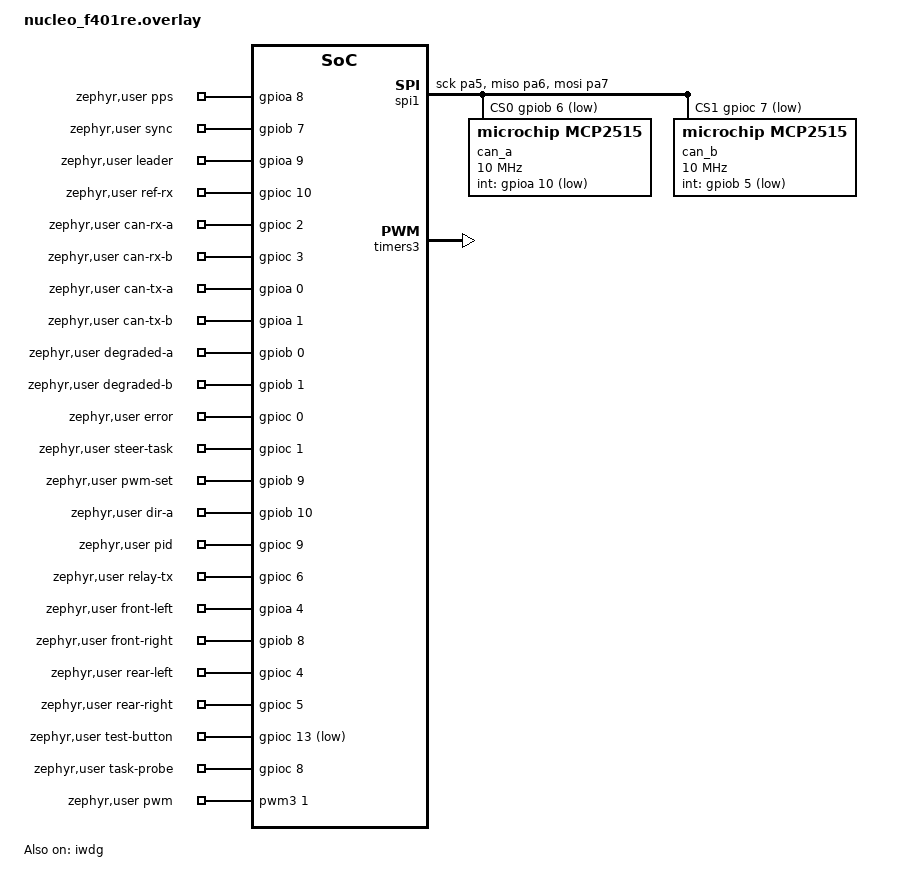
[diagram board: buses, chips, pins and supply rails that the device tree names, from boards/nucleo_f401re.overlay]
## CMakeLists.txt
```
cmake_minimum_required(VERSION 3.28.0)
find_package(Zephyr REQUIRED HINTS $ENV{ZEPHYR_BASE})
project(lab5)
get_filename_component(team_root "${CMAKE_CURRENT_SOURCE_DIR}/../.." ABSOLUTE)
set(lab5 "${team_root}/lab5")
set_property(DIRECTORY APPEND PROPERTY CMAKE_CONFIGURE_DEPENDS "${lab5}/config.json")
execute_process(COMMAND ${PYTHON_EXECUTABLE} "${lab5}/generate_config.py"
    --output "${CMAKE_CURRENT_BINARY_DIR}/lab5_config.h" COMMAND_ERROR_IS_FATAL ANY)
target_include_directories(app PRIVATE "${lab5}/core" "${CMAKE_CURRENT_BINARY_DIR}")
target_sources(app PRIVATE src/lab5_runtime.c "${lab5}/core/lab5.c" "${lab5}/core/clock.c"
    "${lab5}/core/store.c" "${lab5}/core/wire.c" "${lab5}/core/agent.c")
# Reuse the measured baseline's timing instrumentation and workloads, not copies.
set(baseline "${team_root}/lab3_wcet_baseline/lab3_wcet_baseline/stm32_zephyr/src")
target_sources(app PRIVATE src/main.c src/can_protocol.c src/frame_history.c
    src/zone_state.c src/timing_trace.c "${baseline}/timing_stats.c" "${baseline}/timing_probe.c")
target_include_directories(app PRIVATE src "${baseline}")
if(CONFIG_LAB3_ZONE_N3)
    # Lab 2 PID calculation on synthetic samples; no encoder or motor driver.
    set(lab2_pid "${team_root}/bringup/motor_test/src")
    target_sources(app PRIVATE "${baseline}/pid_measurement.c" "${lab2_pid}/velocity_control.c")
    target_include_directories(app PRIVATE "${lab2_pid}")
endif()
if(CONFIG_LAB3_ZONE_N2)
    # Lab 2 calibrated servo mapping from the tracked endpoints.
    set(calibration_file "${team_root}/config/servo_calibration.json")
    set_property(DIRECTORY APPEND PROPERTY CMAKE_CONFIGURE_DEPENDS "${calibration_file}")
    file(READ "${calibration_file}" calibration_json)
    foreach(point LEFT CENTER RIGHT)
        string(TOLOWER "${point}" key)
        string(JSON SERVO_${point}_US GET "${calibration_json}" "${key}_us")
        if(NOT "${SERVO_${point}_US}" MATCHES "^[0-9]+$" OR
           SERVO_${point}_US LESS 500 OR SERVO_${point}_US GREATER 2500)
            message(FATAL_ERROR "Invalid ${key} steering calibration")
        endif()
    endforeach()
    if(NOT ((SERVO_LEFT_US LESS SERVO_CENTER_US AND SERVO_CENTER_US LESS SERVO_RIGHT_US) OR
            (SERVO_LEFT_US GREATER SERVO_CENTER_US AND SERVO_CENTER_US GREATER SERVO_RIGHT_US)))
        message(FATAL_ERROR "Steering center must be between endpoints")
    endif()
    configure_file("${team_root}/stm32_zephyr/src/servo_calibration.h.in"
                   generated/servo_calibration.h @ONLY)
    target_sources(app PRIVATE "${baseline}/steering_measurement.c" "${team_root}/stm32_zephyr/src/servo_core.c")
    target_include_directories(app PRIVATE "${team_root}/stm32_zephyr/src"
                               "${CMAKE_CURRENT_BINARY_DIR}/generated")
endif()
```

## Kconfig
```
mainmenu "Lab 5 time and consensus"
source "Kconfig.zephyr"

config LAB3_ZONE_N2
    bool "Build front steering zone N2"
    help
      SRV servo PWM, front blinkers, FORCE_TX and the RELAY task.

config LAB3_ZONE_N3
    bool "Build rear drivetrain zone N3"
    help
      PWM_OUT motor PWM, DIR_A, PWM_SET, PID workload and rear blinkers.

config LAB3_RELAY
    bool
    default n
    help
      Keep disabled: Lab 5's consensus/discovery relay replaces the Lab 3 relay.

config LAB3_SWAP_CAN_AB
    bool "Logical bus A uses the module on CS PC7 / INT PB5"
    help
      Set for a board whose module A (CS PB6 / INT PA10) is wired to the
      physical bus the other nodes call B. Test points, DEG LEDs and
      heartbeat health bits then follow the physical bus labels.
```

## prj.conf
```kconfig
CONFIG_CAN=y
CONFIG_CAN_INIT_PRIORITY=80
CONFIG_GPIO=y
CONFIG_HWINFO=y
CONFIG_PWM=y
CONFIG_SERIAL=y
CONFIG_CONSOLE=y
CONFIG_UART_CONSOLE=y
CONFIG_PRINTK=y
CONFIG_MAIN_STACK_SIZE=2048
CONFIG_SYSTEM_WORKQUEUE_STACK_SIZE=2048
CONFIG_SYS_CLOCK_TICKS_PER_SEC=10000
CONFIG_CORTEX_M_SYSTICK_64BIT_CYCLE_COUNTER=y
CONFIG_FLASH=y
CONFIG_FLASH_MAP=y
CONFIG_FLASH_LOAD_SIZE=0x40000
CONFIG_POSIX_SYSTEM_INTERFACES=y
CONFIG_POSIX_TIMERS=y
CONFIG_ASSERT=y
CONFIG_WATCHDOG=y
# Main installs the 1 s timeout; avoid the driver's separate boot-time timeout.
CONFIG_WDT_DISABLE_AT_BOOT=y
CONFIG_SPI=y
# Poll short MCP2515 transfers (measured faster than interrupt mode on Oct 21).
CONFIG_SPI_STM32_INTERRUPT=n
CONFIG_CAN_MCP2515=y
CONFIG_CAN_DEFAULT_BITRATE=500000
# One filter per catalog ID, for each controller.
CONFIG_CAN_MAX_FILTER=8
CONFIG_CAN_MCP2515_INT_THREAD_PRIO=2
CONFIG_SHELL=y
CONFIG_SHELL_STACK_SIZE=2048
CONFIG_THREAD_NAME=y
# Crash reports: register dump plus a logged coredump on the serial console.
CONFIG_FAULT_DUMP=2
CONFIG_DEBUG_COREDUMP=y
CONFIG_DEBUG_COREDUMP_BACKEND_LOGGING=y
CONFIG_DEBUG_COREDUMP_MEMORY_DUMP_MIN=y
CONFIG_LOG_PRINTK=n
```

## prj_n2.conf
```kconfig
CONFIG_LAB3_ZONE_N2=y
```

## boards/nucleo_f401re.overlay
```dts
/* Lab 3 Part 5 demo, shared by N2 and N3. Pin record: doc/LAB3_PINOUT.md.
 * CAN modules: SPI1 PA5/PA6/PA7 (XIAO D8 SCK, D9 MISO, D10 MOSI per the
 * handout erratum); module A CS PB6 / INT PA10, module B CS PC7 / INT PB5.
 * CONFIG_LAB3_SWAP_CAN_AB maps logical bus A to module B for a board whose
 * modules are wired to the opposite physical buses.
 */
#include <zephyr/dt-bindings/gpio/gpio.h>
#include <zephyr/dt-bindings/pwm/pwm.h>

/ {
    aliases { can-a = &can_a; can-b = &can_b; };
    zephyr,user {
        pps-gpios = <&gpioa 8 GPIO_ACTIVE_HIGH>;
        sync-gpios = <&gpiob 7 GPIO_ACTIVE_HIGH>;
        leader-gpios = <&gpioa 9 GPIO_ACTIVE_HIGH>;
        ref-rx-gpios = <&gpioc 10 GPIO_ACTIVE_HIGH>;
        can-rx-a-gpios = <&gpioc 2 GPIO_ACTIVE_HIGH>;
        can-rx-b-gpios = <&gpioc 3 GPIO_ACTIVE_HIGH>;
        can-tx-a-gpios = <&gpioa 0 GPIO_ACTIVE_HIGH>;
        can-tx-b-gpios = <&gpioa 1 GPIO_ACTIVE_HIGH>;
        degraded-a-gpios = <&gpiob 0 GPIO_ACTIVE_HIGH>;
        degraded-b-gpios = <&gpiob 1 GPIO_ACTIVE_HIGH>;
        error-gpios = <&gpioc 0 GPIO_ACTIVE_HIGH>;
        /* STEER task-body marker; the SRV test point is the PB4 PWM below. */
        steer-task-gpios = <&gpioc 1 GPIO_ACTIVE_HIGH>;
        pwm-set-gpios = <&gpiob 9 GPIO_ACTIVE_HIGH>;
        dir-a-gpios = <&gpiob 10 GPIO_ACTIVE_HIGH>;
        /* PB11 does not exist on the LQFP64 package (pin 30 is VCAP1). */
        pid-gpios = <&gpioc 9 GPIO_ACTIVE_HIGH>;
        relay-tx-gpios = <&gpioc 6 GPIO_ACTIVE_HIGH>;
        front-left-gpios = <&gpioa 4 GPIO_ACTIVE_HIGH>;
        front-right-gpios = <&gpiob 8 GPIO_ACTIVE_HIGH>;
        rear-left-gpios = <&gpioc 4 GPIO_ACTIVE_HIGH>;
        rear-right-gpios = <&gpioc 5 GPIO_ACTIVE_HIGH>;
        test-button-gpios = <&gpioc 13 GPIO_ACTIVE_LOW>; /* built-in blue B1 */
        task-probe-gpios = <&gpioc 8 GPIO_ACTIVE_HIGH>;
        /* PB4/D5 TIM3_CH1: SRV servo pulse on N2, PWM_OUT motor PWM on N3.
         * Each zone passes its own period at run time. */
        pwms = <&pwm3 1 PWM_MSEC(20) PWM_POLARITY_NORMAL>;
    };
};

&spi1 {
    status = "okay";
    pinctrl-0 = <&spi1_sck_pa5 &spi1_miso_pa6 &spi1_mosi_pa7>;
    pinctrl-names = "default";
    cs-gpios = <&gpiob 6 (GPIO_ACTIVE_LOW | GPIO_PULL_UP)>,
               <&gpioc 7 (GPIO_ACTIVE_LOW | GPIO_PULL_UP)>;
    can_a: mcp2515@0 {
        compatible = "microchip,mcp2515";
        reg = <0>;
        spi-max-frequency = <10000000>; /* MCP2515 max; SPI1 runs 84 MHz/16 = 5.25 MHz */
        int-gpios = <&gpioa 10 GPIO_ACTIVE_LOW>;
        osc-freq = <16000000>;
        status = "okay";
    };
    can_b: mcp2515@1 {
        compatible = "microchip,mcp2515";
        reg = <1>;
        spi-max-frequency = <10000000>;
        int-gpios = <&gpiob 5 GPIO_ACTIVE_LOW>;
        osc-freq = <16000000>;
        status = "okay";
    };
};

/* 84 MHz / (83 + 1) = 1 us ticks: 20000 per servo period, 100 per 10 kHz motor period. */
&timers3 {
    status = "okay";
    st,prescaler = <83>;
    pwm3: pwm {
        status = "okay";
        pinctrl-0 = <&tim3_ch1_pb4>;
        pinctrl-names = "default";
    };
};

/* Board defaults that claim Lab 3 pins: USART1 PB6 (CAN A CS), I2C1 PB8/PB9
 * (FR LED, PWM_SET), I2C3 PA8/PC9 (PID marker), TIM2 PWM PA5 (SPI SCK). */
&usart1 { status = "disabled"; };
&i2c1 { status = "disabled"; };
&i2c3 { status = "disabled"; };
&timers2 { status = "disabled"; };

&iwdg { status = "okay"; };

/* Upper two 128 KiB sectors hold the 30,000-entry two-bank Raft journal.
 * Linker limit prevents firmware from overlapping it. No mass erase on rejoin. */
&flash0 {
    partitions {
        compatible = "fixed-partitions";
        #address-cells = <1>;
        #size-cells = <1>;
        lab5_storage: partition@40000 {
            label = "lab5-raft";
            reg = <0x40000 0x40000>;
        };
    };
};
```

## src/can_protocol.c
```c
/* Lab 3 CAN payload serialization and CRC-8/ATM. Do not send C structs directly. */
#include "can_protocol.h"
#include <string.h>

uint8_t lab3_crc8(const uint8_t *data, unsigned length) {
    uint8_t crc = 0;
    for (unsigned i = 0; i < length; ++i) {
        crc ^= data[i];
        for (unsigned bit = 0; bit < 8; ++bit)
            crc = (crc & 0x80U) ? (uint8_t)((crc << 1) ^ 0x07U) : (uint8_t)(crc << 1);
    }
    return crc;
}

bool lab3_frame_valid(const struct can_frame *frame) {
    return frame && !(frame->flags & (CAN_FRAME_IDE | CAN_FRAME_RTR | CAN_FRAME_FDF)) &&
           frame->dlc == 8 && lab3_crc8(frame->data, 7) == frame->data[7];
}

void lab3_seal(struct can_frame *frame) {
    frame->dlc = 8;
    frame->data[7] = lab3_crc8(frame->data, 7);
}

static void start(struct can_frame *f, uint32_t id) {
    memset(f, 0, sizeof(*f));
    f->id = id;
    f->dlc = 8;
}

void lab3_pack_heartbeat(struct can_frame *f, uint32_t id, uint8_t state, bool a, bool b) {
    start(f, id);
    f->data[1] = state;
    f->data[2] = (a ? 1 : 0) | (b ? 2 : 0);
}

void lab3_pack_fault(struct can_frame *f, uint8_t failing_zone, enum fault_reason reason,
                     uint8_t reporter) {
    start(f, ID_FAULT);
    f->data[1] = failing_zone;
    f->data[2] = (uint8_t)reason;
    f->data[3] = reporter;
}

void lab3_pack_force(struct can_frame *f, int8_t counter) {
    start(f, ID_FORCE);
    f->data[1] = (uint8_t)counter;
}

bool lab3_ctrl_decode(const struct can_frame *f, struct lab3_ctrl *out) {
    /* b0 seq/flags, b1..2 steer LE, b3 throttle %, b4 brake %, b5 buttons, b6 reserved. */
    if ((f->data[0] >> 4) != CTRL_FLAGS || f->data[6] != 0 || f->data[3] > 100 || f->data[4] > 100)
        return false;
    out->steer = (int16_t)(f->data[1] | (f->data[2] << 8));
    out->throttle = f->data[3];
    out->brake = f->data[4];
    out->buttons = f->data[5];
    return true;
}

uint8_t lab3_heartbeat_zone(uint32_t id) {
    switch (id) {
    case ID_HB_N1:
        return ZONE_N1;
    case ID_HB_N2:
        return ZONE_N2;
    case ID_HB_N3:
        return ZONE_N3;
    default:
        return 0;
    }
}

uint8_t lab3_frame_origin(const struct can_frame *f) {
    switch (f->id) {
    case ID_CTRL:
    case ID_BLINK:
    case ID_HB_N1:
        return ZONE_N1;
    case ID_HB_N2:
    case ID_FORCE:
        return ZONE_N2;
    case ID_HB_N3:
        return ZONE_N3;
    case ID_FAULT:
        return f->data[3] >= ZONE_N1 && f->data[3] <= ZONE_N3 ? f->data[3] : 0;
    default:
        return 0;
    }
}

uint8_t lab3_dedup_source(const struct can_frame *f) { return f->id == ID_FAULT ? f->data[3] : 0; }
```

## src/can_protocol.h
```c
#ifndef LAB3_DEMO_CAN_PROTOCOL_H
#define LAB3_DEMO_CAN_PROTOCOL_H
/* Lab 3 template catalog wire format; pi/can_protocol.py is the other half.
 * Standard IDs, DLC 8. Byte 0: low nibble per-ID sequence, high nibble flags.
 * Byte 7: CRC-8/ATM (poly 0x07, init 0) over bytes 0..6. */
#include <stdbool.h>
#include <stdint.h>
#include <zephyr/drivers/can.h>

#define ID_CTRL 0x010
#define ID_FAULT 0x020
#define ID_HB_N1 0x100
#define ID_HB_N2 0x101
#define ID_HB_N3 0x102
#define ID_BLINK 0x200
#define ID_FORCE 0x300
#define ZONE_N1 1
#define ZONE_N2 2
#define ZONE_N3 3
#define STATE_ERROR 0
#define STATE_OK 1
#define BLINK_OFF 0
#define BLINK_LEFT 1
#define BLINK_RIGHT 2
#define BLINK_HAZARD 3
#define CTRL_FLAGS 1 /* required high nibble of CTRL byte 0 */

/* FAULT byte 2. Clear releases every latch; ZONE_LOST is informational because
 * each receiver detects heartbeat loss itself and must recover without a clear. */
enum fault_reason {
    FAULT_CLEAR = 0,
    FAULT_TEST_BUTTON = 1,
    FAULT_BAD_CRC = 2,
    FAULT_BAD_CTRL = 3,
    FAULT_ZONE_LOST = 4,
};

/* Team-defined CTRL value ranges: steering is any int16; pedals are 0..100 %. */
struct lab3_ctrl {
    int16_t steer;
    uint8_t throttle, brake, buttons;
};

uint8_t lab3_crc8(const uint8_t *data, unsigned length);
/* Standard data frame, DLC 8 and matching CRC. */
bool lab3_frame_valid(const struct can_frame *frame);
void lab3_seal(struct can_frame *frame);
/* Builders leave the sequence nibble zero; the send helper assigns it and seals. */
void lab3_pack_heartbeat(struct can_frame *frame, uint32_t id, uint8_t state, bool bus_a_ok,
                         bool bus_b_ok);
/* FAULT bytes 1..3: failing zone, reason, reporting zone. */
void lab3_pack_fault(struct can_frame *frame, uint8_t failing_zone, enum fault_reason reason,
                     uint8_t reporter);
void lab3_pack_force(struct can_frame *frame, int8_t counter);
/* Decodes a CRC-valid CTRL; false when any field is outside the values table. */
bool lab3_ctrl_decode(const struct can_frame *frame, struct lab3_ctrl *out);
/* Zone whose heartbeat this ID is, or 0. */
uint8_t lab3_heartbeat_zone(uint32_t id);
/* Zone that originated this frame (FAULT: reporter), or 0 when unknown. */
uint8_t lab3_frame_origin(const struct can_frame *frame);
/* FAULT has several senders with independent sequence counters. */
uint8_t lab3_dedup_source(const struct can_frame *frame);
#endif
```

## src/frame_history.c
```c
#include "frame_history.h"

static bool same(struct frame_key a, struct frame_key b) {
    return a.id == b.id && a.source == b.source && a.seq == b.seq;
}
static bool live(const struct frame_record *r, uint32_t now) {
    return r->valid && (uint32_t)(now - r->first_ms) <= FRAME_HISTORY_MS;
}
enum frame_observation frame_observe(struct frame_history *h, struct frame_key key, unsigned bus,
                                     uint32_t received_ms) {
    struct frame_record *free_slot = 0;
    if (bus > 1)
        return FRAME_HISTORY_FULL;
    for (unsigned i = 0; i < FRAME_HISTORY_SIZE; ++i) {
        struct frame_record *r = &h->records[i];
        if (!live(r, received_ms)) {
            if (!free_slot)
                free_slot = r;
        } else if (same(r->key, key)) {
            r->seen_buses |= (uint8_t)(1U << bus);
            /* Do not extend expiry on a duplicate: repeats cannot keep a key
             * alive forever and suppress a new sequence generation. */
            return FRAME_DUPLICATE;
        }
    }
    /* Never evict live history to make room: that could re-admit a duplicate. */
    if (!free_slot)
        return FRAME_HISTORY_FULL;
    *free_slot = (struct frame_record){
        .key = key, .first_ms = received_ms, .seen_buses = (uint8_t)(1U << bus), .valid = true};
    return FRAME_NEW;
}
enum relay_claim frame_claim_relay(struct frame_history *h, struct frame_key key,
                                   unsigned incoming_bus, uint32_t first_ms, uint32_t now_ms) {
    if (incoming_bus > 1)
        return RELAY_STALE;
    const uint8_t destination = (uint8_t)(1U << (incoming_bus ^ 1U));
    for (unsigned i = 0; i < FRAME_HISTORY_SIZE; ++i) {
        struct frame_record *r = &h->records[i];
        if (!live(r, now_ms) || !same(r->key, key) || r->first_ms != first_ms)
            continue;
        if ((r->seen_buses | r->attempted_buses) & destination)
            return RELAY_SUPPRESS;
        r->attempted_buses |= destination;
        return RELAY_SEND;
    }
    /* Do not forward an expired queue entry using a newer generation's record. */
    return RELAY_STALE;
}
```

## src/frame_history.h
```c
#ifndef LAB3_FRAME_HISTORY_H
#define LAB3_FRAME_HISTORY_H
#include <stdbool.h>
#include <stdint.h>

/* Ported from Tianyi's lab3-relay-immediate branch (commit a146752).
 *
 * Duplicate lifetime, NOT a wait before forwarding. It must exceed the worst
 * skew between the A copy, the B copy and a relayed copy (the measured Pi gap
 * between its can0 and can1 writes reaches 2.6 ms) and stay below the 320 ms
 * reuse time of a 4-bit sequence at 20 ms. Every catalog payload is idempotent,
 * so a copy that arrives after expiry is re-applied harmlessly.
 */
#define FRAME_HISTORY_MS 20U
#define FRAME_HISTORY_SIZE 32U
struct frame_key {
    uint16_t id;
    uint8_t source, seq;
};
struct frame_record {
    struct frame_key key;
    uint32_t first_ms;
    uint8_t seen_buses, attempted_buses;
    bool valid;
};
struct frame_history {
    struct frame_record records[FRAME_HISTORY_SIZE];
};
enum frame_observation { FRAME_NEW, FRAME_DUPLICATE, FRAME_HISTORY_FULL };
enum relay_claim { RELAY_SEND, RELAY_SUPPRESS, RELAY_STALE };

/* Caller serializes all access. Only validated catalog frames may enter.
 * A same-bus repeat inside the lifetime is a relayed copy and is dropped; after
 * the lifetime the same (ID, seq) is a new message. */
enum frame_observation frame_observe(struct frame_history *h, struct frame_key key, unsigned bus,
                                     uint32_t received_ms);
/* Claim at most one attempt on the opposite bus. No heartbeat state is used.
 * first_ms is the original receive timestamp carried with the queued frame.
 * A known opposite-bus copy suppresses the send. */
enum relay_claim frame_claim_relay(struct frame_history *h, struct frame_key key,
                                   unsigned incoming_bus, uint32_t first_ms, uint32_t now_ms);
#endif
```

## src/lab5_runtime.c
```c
#include "lab5_runtime.h"
#include "agent.h"
#include "lab5.h"
#include "lab5_config.h"
#include "store.h"
#include <string.h>
#include <time.h>
#include <zephyr/drivers/flash.h>
#include <zephyr/drivers/gpio.h>
#include <zephyr/kernel.h>
#include <zephyr/shell/shell.h>
#include <zephyr/shell/shell_uart.h>
#include <zephyr/storage/flash_map.h>
#include <zephyr/sys/printk.h>

static struct l5_raft raft;
static struct l5_store store;
static struct l5_clock net_clock;
static struct l5_wire wire;
static struct l5_agent agent;
static const struct flash_area *area;
static void (*send_frame)(unsigned, const struct can_frame *);
K_MUTEX_DEFINE(raft_lock);
void lab5_console_print(const char *format, ...) {
    va_list args;
    va_start(args, format);
    /* Use the shell's UART writer for both diagnostics and command output.
     * A separate printk mutex cannot serialize against shell echo/prompt TX.
     * Only startup messages use printk before the shell becomes active. */
    const struct shell *sh = shell_backend_uart_get_ptr();
    if (shell_ready(sh))
        shell_vfprintf(sh, SHELL_NORMAL, format, args);
    else
        vprintk(format, args);
    va_end(args);
}
K_SEM_DEFINE(ready, 0, 1);
K_MSGQ_DEFINE(applied_queue, 8, 128, 4);
struct pps_row {
    uint64_t global, raw;
    int64_t rate_ppb, correction;
    uint8_t node;
};
K_MSGQ_DEFINE(pps_queue, sizeof(struct pps_row), 4, 8);
struct debug_row {
    uint16_t term, index, commit;
    uint8_t type, src, dst, role, leader, failed;
};
K_MSGQ_DEFINE(debug_queue, sizeof(struct debug_row), 64, 4);
struct health_row {
    uint64_t raw;
    uint32_t age[3];
    unsigned reasons, node;
};
K_MSGQ_DEFINE(health_queue, sizeof(struct health_row), 16, 8);
struct log_row {
    uint16_t index, term;
    uint8_t event, replay, pad[2];
};
static uint32_t log_drops;
static const struct gpio_dt_spec pps = GPIO_DT_SPEC_GET(DT_PATH(zephyr_user), pps_gpios);
static const struct gpio_dt_spec leader_pin = GPIO_DT_SPEC_GET(DT_PATH(zephyr_user), leader_gpios);
static const struct gpio_dt_spec sync_pin = GPIO_DT_SPEC_GET(DT_PATH(zephyr_user), sync_gpios);
static const struct gpio_dt_spec ref_pin = GPIO_DT_SPEC_GET(DT_PATH(zephyr_user), ref_rx_gpios);
uint64_t lab5_raw_us(void) { return k_cyc_to_us_floor64(k_cycle_get_64()); }
static bool flash_read_cb(void *ctx, uint32_t off, void *p, size_t n) {
    ARG_UNUSED(ctx);
    return flash_area_read(area, off, p, n) == 0;
}
static bool flash_write_cb(void *ctx, uint32_t off, const void *p, size_t n) {
    ARG_UNUSED(ctx);
    return flash_area_write(area, off, p, n) == 0;
}
static bool flash_erase_cb(void *ctx, unsigned bank) {
    ARG_UNUSED(ctx);
    return flash_area_erase(area, bank * L5_BANK_SIZE, L5_BANK_SIZE) == 0;
}
static bool read_entry(void *ctx, uint16_t i, struct l5_entry *e) {
    ARG_UNUSED(ctx);
    return l5_store_read(&store, i, e);
}
static bool append_entry(void *ctx, struct l5_entry e) {
    ARG_UNUSED(ctx);
    return l5_store_append(&store, e);
}
static bool truncate_entries(void *ctx, uint16_t i) {
    ARG_UNUSED(ctx);
    return l5_store_truncate(&store, i);
}
static bool hard_state(void *ctx, uint16_t t, uint8_t v) {
    ARG_UNUSED(ctx);
    return l5_store_hardstate(&store, t, v);
}
static void send_packet(void *ctx, unsigned bus, const struct l5_packet *p) {
    ARG_UNUSED(ctx);
    struct can_frame f = {.id = p->id, .dlc = 8};
    memcpy(f.data, p->data, 8);
    if (p->id == 0x80U + raft.id) {
        /* A durable operation in this tick may have delayed REF creation.
         * Stamp our own reference at enqueue time; preserve relayed origins. */
        uint32_t stamp = (uint32_t)l5_global(&net_clock, lab5_raw_us());
        for (unsigned i = 0; i < 4; i++)
            f.data[3 + i] = (uint8_t)(stamp >> (8 * i));
        f.data[7] = l5_crc(f.data, 7);
    }
    if (send_frame)
        send_frame(bus, &f);
}
static void send_rpc(void *ctx, const struct l5_rpc *m) {
    ARG_UNUSED(ctx);
    l5_agent_rpc(&agent, m);
    if (L5_CFG_DEBUG) {
        struct debug_row row = {m->term, m->index,  m->commit,   m->type,    m->src,
                                m->dst,  raft.role, raft.leader, raft.failed};
        if (k_msgq_put(&debug_queue, &row, K_NO_WAIT))
            log_drops++;
    }
}
static void on_apply(void *ctx, uint16_t i, struct l5_entry e, bool replay) {
    ARG_UNUSED(ctx);
    struct log_row row = {.index = i, .term = e.term, .event = e.event, .replay = replay};
    if (k_msgq_put(&applied_queue, &row, K_NO_WAIT))
        log_drops++;
}
int lab5_runtime_init(unsigned id, void (*send)(unsigned, const struct can_frame *)) {
    send_frame = send;
    int rc = flash_area_open(FIXED_PARTITION_ID(lab5_storage), &area);
    if (rc)
        return rc;
    if (area->fa_size != L5_STORE_SIZE)
        return -EINVAL;
    struct l5_flash_io flash = {NULL, flash_read_cb, flash_write_cb, flash_erase_cb};
    if (!l5_store_open(&store, flash))
        return -EIO;
    /* Sector erases stall this single-bank MCU. Reclaim obsolete entries and
     * full journals only before tasks/watchdog start; runtime store updates
     * program fresh words and preserve the same logical entries/term/vote. */
    uint32_t generation = store.generation;
    if (!l5_store_prepare_boot(&store))
        return -EIO;
    if (store.generation != generation)
        lab5_console_print("STORE boot_compaction preserved term=%u vote=%u entries=%u\n",
               store.term, store.vote, store.length);
    const struct gpio_dt_spec *pins[] = {&pps, &leader_pin, &sync_pin, &ref_pin};
    for (unsigned i = 0; i < ARRAY_SIZE(pins); i++) {
        if (!gpio_is_ready_dt(pins[i]))
            return -ENODEV;
        rc = gpio_pin_configure_dt(pins[i], GPIO_OUTPUT_INACTIVE);
        if (rc)
            return rc;
    }
    l5_clock_init(&net_clock, lab5_raw_us());
    l5_agent_init(&agent, &raft, &net_clock, &wire, NULL, send_packet, L5_CFG_CAN_DELAY_US);
    struct l5_config cfg = {L5_CFG_HEARTBEAT_MS, L5_CFG_APPEND_MS, L5_CFG_MISSED_HEARTBEATS,
                            L5_CFG_JITTER_MS,    L5_CFG_CAPACITY,  L5_CFG_DEFAULT_LEADER,
                            L5_CFG_SEED,         L5_CFG_DEBUG};
    struct l5_io io = {NULL,       read_entry, append_entry, truncate_entries,
                       hard_state, send_rpc,   on_apply};
    return l5_init(&raft, id, cfg, io, store.term, store.vote, store.length, lab5_raw_us() / 1000)
               ? 0
               : -EIO;
}
void lab5_ready(void) { k_sem_give(&ready); }
void lab5_pause(bool paused) {
    k_mutex_lock(&raft_lock, K_FOREVER);
    agent.paused = paused;
    k_mutex_unlock(&raft_lock);
}
bool lab5_runtime_receive(unsigned bus, const struct can_frame *f, uint64_t raw) {
    if (f->flags & (CAN_FRAME_IDE | CAN_FRAME_RTR) || f->dlc != 8)
        return false;
    struct l5_packet p = {.id = (uint16_t)f->id};
    memcpy(p.data, f->data, 8);
    k_mutex_lock(&raft_lock, K_FOREVER);
    uint32_t samples = net_clock.samples;
    uint64_t processed = lab5_raw_us();
    uint32_t delay = agent.delay_us;
    agent.delay_us += (uint32_t)(processed - raw);
    bool used = l5_agent_receive(&agent, bus, &p, processed);
    agent.delay_us = delay;
    if (net_clock.samples != samples) {
        gpio_pin_toggle_dt(&ref_pin);
        uint64_t global = l5_global(&net_clock, lab5_raw_us());
        struct timespec t = {.tv_sec = (time_t)(global / 1000000),
                             .tv_nsec = (long)(global % 1000000) * 1000};
        (void)clock_settime(CLOCK_REALTIME, &t); /* uptime/cycle clock is unchanged */
    }
    k_mutex_unlock(&raft_lock);
    return used;
}
uint64_t lab5_global_us(void) {
    k_mutex_lock(&raft_lock, K_FOREVER);
    uint64_t t = l5_global(&net_clock, lab5_raw_us());
    k_mutex_unlock(&raft_lock);
    return t;
}
bool lab5_error(void) {
    k_mutex_lock(&raft_lock, K_FOREVER);
    bool e = l5_agent_error(&agent, lab5_raw_us());
    k_mutex_unlock(&raft_lock);
    return e;
}
unsigned lab5_hazard_hz(void) {
    k_mutex_lock(&raft_lock, K_FOREVER);
    unsigned hz = l5_agent_hazard_hz(&agent, lab5_raw_us());
    k_mutex_unlock(&raft_lock);
    return hz;
}
static void protocol_thread(void *a, void *b, void *c) {
    ARG_UNUSED(a);
    ARG_UNUSED(b);
    ARG_UNUSED(c);
    k_sem_take(&ready, K_FOREVER);
    uint64_t last_second = 0, pulse_end = 0;
    uint16_t previous_term = 0;
    uint8_t previous_role = 255;
    unsigned previous_health = UINT32_MAX;
    while (true) {
        k_mutex_lock(&raft_lock, K_FOREVER);
        /* Reception can move the clock anchor while this task waits. Read raw
         * only after acquiring ownership, then refresh after durable writes. */
        uint64_t raw = lab5_raw_us();
        agent.upstream_ok = true;
        l5_agent_tick(&agent, raw);
        raw = lab5_raw_us();
        unsigned reasons = l5_agent_error_reason(&agent, raw);
        if (reasons != previous_health) {
            struct health_row h = {.raw = raw, .reasons = reasons, .node = raft.id};
            for (unsigned n = 1; n <= 3; n++)
                h.age[n - 1] = l5_agent_report_age(&agent, n, raw);
            if (k_msgq_put(&health_queue, &h, K_NO_WAIT))
                log_drops++;
            previous_health = reasons;
        }
        uint64_t global = l5_global(&net_clock, raw);
        gpio_pin_set_dt(&leader_pin, raft.role == L5_LEADER && !agent.paused && !raft.failed);
        gpio_pin_set_dt(&sync_pin, l5_agent_synced(&agent, raw));
        if (global / 1000000 != last_second) {
            last_second = global / 1000000;
            pulse_end = raw + 1000;
            gpio_pin_set_dt(&pps, 1);
            struct pps_row row = {
                global, raw, (int64_t)((net_clock.rate - 1.0) * 1e9),
                (int64_t)((raw - net_clock.local_anchor) * (net_clock.rate - 1.0)), raft.id};
            if (k_msgq_put(&pps_queue, &row, K_NO_WAIT))
                log_drops++;
        }
        if (raw >= pulse_end)
            gpio_pin_set_dt(&pps, 0);
        if (raft.term != previous_term || raft.role != previous_role) {
            struct debug_row row = {raft.term, raft.length, raft.commit, 0,          raft.id,
                                    0,         raft.role,   raft.leader, raft.failed};
            if (k_msgq_put(&debug_queue, &row, K_NO_WAIT))
                log_drops++;
            previous_term = raft.term;
            previous_role = raft.role;
        }
        k_mutex_unlock(&raft_lock);
        k_sleep(K_USEC(200));
    }
}
K_THREAD_DEFINE(protocol_tid, 3072, protocol_thread, NULL, NULL, NULL, 2, 0, 0);
static void log_thread(void *a, void *b, void *c) {
    ARG_UNUSED(a);
    ARG_UNUSED(b);
    ARG_UNUSED(c);
    struct log_row row;
    while (true) {
        if (!k_msgq_get(&applied_queue, &row, K_MSEC(10)))
            lab5_console_print("COMMIT index=%u term=%u event=%s replayed=%u\n", row.index, row.term,
                   l5_event_name(row.event), row.replay);
        struct pps_row p;
        while (!k_msgq_get(&pps_queue, &p, K_NO_WAIT))
            lab5_console_print("PPS node=%u global_us=%llu local_us=%llu rate_ppb=%lld correction_us=%lld\n",
                   p.node, (unsigned long long)p.global, (unsigned long long)p.raw,
                   (long long)p.rate_ppb, (long long)p.correction);
        struct debug_row d;
        struct health_row h;
        for (unsigned i = 0; i < 4 && !k_msgq_get(&health_queue, &h, K_NO_WAIT); i++)
            lab5_console_print("HEALTH node=%u local_us=%llu reasons=0x%x "
                               "report_age_ms=%u,%u,%u log_drops=%u\n",
                               h.node, (unsigned long long)h.raw, h.reasons,
                               h.age[0], h.age[1], h.age[2], log_drops);
        /* A debug burst must not postpone committed entries indefinitely. */
        for (unsigned i = 0; i < 8 && !k_msgq_get(&debug_queue, &d, K_NO_WAIT); i++)
            lab5_console_print("RAFT type=%u src=%u dst=%u term=%u index=%u commit=%u role=%u leader=%u "
                   "failed=%u log_drops=%u\n",
                   d.type, d.src, d.dst, d.term, d.index, d.commit, d.role, d.leader, d.failed,
                   log_drops);
    }
}
K_THREAD_DEFINE(log_tid, 1024, log_thread, NULL, NULL, NULL, 11, 0, 0);
static int network_cmd(const struct shell *sh, size_t argc, char **argv) {
    ARG_UNUSED(sh);
    ARG_UNUSED(argc);
    ARG_UNUSED(argv);
    k_mutex_lock(&raft_lock, K_FOREVER);
    uint8_t node = raft.id, leader = raft.leader;
    uint16_t term = raft.term, commit = raft.commit;
    struct l5_graph graph = raft.graph;
    k_mutex_unlock(&raft_lock);
    lab5_console_print(
                "NETWORK node=%u term=%u leader=%u commit=%u nodes=0x%x links=0x%x cockpit_ok=%u\n",
                node, term, leader, commit, graph.nodes, graph.links, graph.cockpit_ok);
    return 0;
}
static int log_cmd(const struct shell *sh, size_t argc, char **argv) {
    ARG_UNUSED(sh);
    ARG_UNUSED(argc);
    ARG_UNUSED(argv);
    k_mutex_lock(&raft_lock, K_FOREVER);
    uint16_t end = raft.commit;
    uint8_t node = raft.id;
    k_mutex_unlock(&raft_lock);
    lab5_console_print("LOG_BEGIN node=%u through_index=%u\n", node, end);
    /* Committed entries are immutable. Snapshot the end once and copy each
     * entry under the lock, but never hold it across slow UART output. This
     * also permits a storage-bank switch between reads without racing one. */
    for (uint16_t i = 1; i <= end; i++) {
        struct l5_entry e;
        k_mutex_lock(&raft_lock, K_FOREVER);
        bool ok = l5_store_read(&store, i, &e);
        k_mutex_unlock(&raft_lock);
        if (!ok) {
            lab5_console_print("LOG_ERROR node=%u index=%u through_index=%u\n", node, i, end);
            return -EIO;
        }
        lab5_console_print("LOG index=%u term=%u event=%s\n", i, e.term, l5_event_name(e.event));
    }
    lab5_console_print("LOG_END node=%u through_index=%u entries=%u\n", node, end, end);
    return 0;
}
static int event_cmd(const struct shell *sh, size_t argc, char **argv) {
    ARG_UNUSED(sh);
    ARG_UNUSED(argc);
    ARG_UNUSED(argv);
    k_mutex_lock(&raft_lock, K_FOREVER);
    bool queued = l5_user_event(&raft);
    k_mutex_unlock(&raft_lock);
    lab5_console_print("EVENT %s\n",
                queued ? "queued; wait for COMMIT"
                       : "not queued: no leader, catching up, or storage full");
    return queued ? 0 : -EAGAIN;
}
SHELL_STATIC_SUBCMD_SET_CREATE(
    lab5_sub, SHELL_CMD(network, NULL, "Committed getNetwork snapshot", network_cmd),
    SHELL_CMD(log, NULL, "Dump committed log (use while idle)", log_cmd),
    SHELL_CMD(event, NULL, "Queue one replicated EVENT from this node", event_cmd),
    SHELL_SUBCMD_SET_END);
SHELL_CMD_REGISTER(lab5, &lab5_sub, "Lab 5 consensus diagnostics", NULL);
```

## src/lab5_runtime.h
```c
#ifndef LAB5_RUNTIME_H
#define LAB5_RUNTIME_H
#include <zephyr/drivers/can.h>
#include <zephyr/toolchain.h>
/* Thread-only console output; never called from CAN/protocol hot paths. */
__printf_like(1, 2) void lab5_console_print(const char *format, ...);
int lab5_runtime_init(unsigned id, void (*send)(unsigned, const struct can_frame *));
bool lab5_runtime_receive(unsigned bus, const struct can_frame *, uint64_t raw_us);
uint64_t lab5_raw_us(void);
uint64_t lab5_global_us(void);
bool lab5_error(void);
unsigned lab5_hazard_hz(void);
void lab5_pause(bool paused);
void lab5_ready(void);
#endif
```

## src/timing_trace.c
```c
/* GPIO LEDs and test points; every pin starts inactive (low). */
#include "timing_trace.h"
#include <errno.h>
#include <zephyr/devicetree.h>
#include <zephyr/drivers/gpio.h>
#include <zephyr/sys/atomic.h>
#include <zephyr/sys/util.h>

#define USER DT_PATH(zephyr_user)
static const struct gpio_dt_spec pins[] = {
    [TP_CAN_RX_A] = GPIO_DT_SPEC_GET(USER, can_rx_a_gpios),
    [TP_CAN_RX_B] = GPIO_DT_SPEC_GET(USER, can_rx_b_gpios),
    [TP_CAN_TX_A] = GPIO_DT_SPEC_GET(USER, can_tx_a_gpios),
    [TP_CAN_TX_B] = GPIO_DT_SPEC_GET(USER, can_tx_b_gpios),
    [TP_DEG_A] = GPIO_DT_SPEC_GET(USER, degraded_a_gpios),
    [TP_DEG_B] = GPIO_DT_SPEC_GET(USER, degraded_b_gpios),
    [TP_ERR] = GPIO_DT_SPEC_GET(USER, error_gpios),
    [TP_STEER] = GPIO_DT_SPEC_GET(USER, steer_task_gpios),
    [TP_PWM_SET] = GPIO_DT_SPEC_GET(USER, pwm_set_gpios),
    [TP_DIR_A] = GPIO_DT_SPEC_GET(USER, dir_a_gpios),
    [TP_PID] = GPIO_DT_SPEC_GET(USER, pid_gpios),
    [TP_FL] = GPIO_DT_SPEC_GET(USER, front_left_gpios),
    [TP_FR] = GPIO_DT_SPEC_GET(USER, front_right_gpios),
    [TP_RL] = GPIO_DT_SPEC_GET(USER, rear_left_gpios),
    [TP_RR] = GPIO_DT_SPEC_GET(USER, rear_right_gpios),
    [TP_RELAY_TX] = GPIO_DT_SPEC_GET(USER, relay_tx_gpios),
    [TP_TASK_PROBE] = GPIO_DT_SPEC_GET(USER, task_probe_gpios),
};
/* Toggles come from several threads; one atomic bit per pin keeps levels consistent. */
static atomic_t levels;

int lab3_trace_init(void) {
    for (unsigned i = 0; i < ARRAY_SIZE(pins); ++i) {
        if (!gpio_is_ready_dt(&pins[i]))
            return -ENODEV;
        int rc = gpio_pin_configure_dt(&pins[i], GPIO_OUTPUT_INACTIVE);
        if (rc)
            return rc;
    }
    return 0;
}

void lab3_trace_toggle(unsigned i) {
    if (i >= ARRAY_SIZE(pins))
        return;
    bool was = (atomic_xor(&levels, BIT(i)) & BIT(i)) != 0;
    (void)gpio_pin_set_dt(&pins[i], !was);
}

void lab3_trace_set(unsigned i, int active) {
    if (i >= ARRAY_SIZE(pins))
        return;
    atomic_set_bit_to(&levels, i, active);
    (void)gpio_pin_set_dt(&pins[i], !!active);
}
```

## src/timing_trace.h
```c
#ifndef LAB3_TIMING_TRACE_H
#define LAB3_TIMING_TRACE_H
#include <stdint.h>
/* Same API and index layout as the baseline's timing_trace.h, because the reused
 * baseline timing_probe.c drives index 16. Pins: boards/nucleo_f401re.overlay. */
enum lab3_test_point {
    TP_CAN_RX_A,
    TP_CAN_RX_B,
    TP_CAN_TX_A,
    TP_CAN_TX_B,
    TP_DEG_A,
    TP_DEG_B,
    TP_ERR,
    TP_STEER,
    TP_PWM_SET,
    TP_DIR_A,
    TP_PID,
    TP_FL,
    TP_FR,
    TP_RL,
    TP_RR,
    TP_RELAY_TX,
    TP_TASK_PROBE,
};
int lab3_trace_init(void);
void lab3_trace_toggle(unsigned index);
void lab3_trace_set(unsigned index, int active);
#endif
```

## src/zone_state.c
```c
#include "zone_state.h"
#include <string.h>

void zone_monitor_init(struct zone_monitor *m, uint8_t self, uint32_t now_ms) {
    memset(m, 0, sizeof(*m));
    m->self = self;
    m->traffic_ms[0] = m->traffic_ms[1] = now_ms;
}

void zone_monitor_heartbeat(struct zone_monitor *m, uint8_t zone, unsigned bus, uint32_t now_ms) {
    if (zone == 0 || zone >= ZONE_SLOTS || zone == m->self || bus > 1)
        return;
    m->hb_seen[zone][bus] = true;
    m->hb_ms[zone][bus] = now_ms;
}

void zone_monitor_traffic(struct zone_monitor *m, unsigned bus, uint32_t now_ms) {
    if (bus <= 1)
        m->traffic_ms[bus] = now_ms;
}

void zone_monitor_ctrl(struct zone_monitor *m) { m->ctrl_seen = true; }

static bool fresh(bool seen, uint32_t stamp, uint32_t now, uint32_t limit) {
    return seen && (uint32_t)(now - stamp) < limit;
}

bool zone_monitor_present(const struct zone_monitor *m, uint8_t zone, unsigned bus,
                          uint32_t now_ms) {
    if (zone == 0 || zone >= ZONE_SLOTS || zone == m->self || bus > 1)
        return false;
    return fresh(m->hb_seen[zone][bus], m->hb_ms[zone][bus], now_ms, BUS_SILENT_MS);
}

struct zone_health zone_monitor_evaluate(const struct zone_monitor *m, uint32_t now) {
    struct zone_health h = {0};
    bool all_alive = true, heard = false;
    for (uint8_t zone = 1; zone < ZONE_SLOTS; ++zone) {
        if (zone == m->self)
            continue;
        for (unsigned bus = 0; bus < 2; ++bus) {
            h.alive[zone] |= fresh(m->hb_seen[zone][bus], m->hb_ms[zone][bus], now, ZONE_FAIL_MS);
            heard |= fresh(m->hb_seen[zone][bus], m->hb_ms[zone][bus], now, BUS_SILENT_MS);
        }
        all_alive &= h.alive[zone];
    }
    for (unsigned bus = 0; bus < 2; ++bus)
        h.bus_ok[bus] = fresh(true, m->traffic_ms[bus], now, BUS_SILENT_MS);
    for (unsigned bus = 0; bus < 2; ++bus)
        h.degraded[bus] = !h.bus_ok[bus] && h.bus_ok[bus ^ 1U];
    h.isolated = !heard;
    h.error = m->latched || !all_alive || h.isolated || !m->ctrl_seen;
    return h;
}

uint32_t zone_monitor_next_change_ms(const struct zone_monitor *m, uint32_t now) {
    uint32_t next = UINT32_MAX;
    for (unsigned bus = 0; bus < 2; ++bus) {
        uint32_t age = now - m->traffic_ms[bus];
        if (age < BUS_SILENT_MS && BUS_SILENT_MS - age < next)
            next = BUS_SILENT_MS - age;
    }
    return next;
}
```

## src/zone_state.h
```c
#ifndef LAB3_ZONE_STATE_H
#define LAB3_ZONE_STATE_H
#include <stdbool.h>
#include <stdint.h>

/* Every supervision threshold lives here; pi/zone_state.py mirrors them.
 * R4.5: heartbeat every 20 ms (+/-10 %); a zone fails only after three
 * consecutive missed heartbeats on both buses, 3 x 22 ms = 66 ms at the period
 * limit (the clarification's error chain uses the same 66 ms).
 * R4.7: a bus is degraded after three heartbeat periods (60 ms) without traffic
 * from any other node while the other bus still has traffic; a zone that hears
 * no heartbeat from any other zone on either bus for 60 ms is isolated. */
#define HB_PERIOD_MS 20U
#define ZONE_FAIL_MS 66U
#define BUS_SILENT_MS 60U
/* BLINK arrives at least every 500 ms; older than this, N1 is unreachable. */
#define BLINK_TIMEOUT_MS 750U
#define ZONE_SLOTS 4U /* indexed by zone id 1..3 */

/* Owned by one lock holder per node. Times are wrapping uptime milliseconds. */
struct zone_monitor {
    uint8_t self;
    bool hb_seen[ZONE_SLOTS][2];
    uint32_t hb_ms[ZONE_SLOTS][2];
    uint32_t traffic_ms[2]; /* last frame from any other node; boot time until then */
    bool ctrl_seen;         /* R3: one valid CTRL is needed to leave power-up error */
    /* Test button, bad CTRL or a received FAULT; only a FAULT clear releases it. */
    bool latched;
};

struct zone_health {
    bool alive[ZONE_SLOTS]; /* peer heartbeat within ZONE_FAIL_MS on some bus */
    bool bus_ok[2];         /* traffic within BUS_SILENT_MS; heartbeat health bits */
    bool degraded[2];       /* R4.7 per-bus status LED */
    bool isolated;          /* R4.7: own fail-safe (motor braked, steering held, hazards) */
    bool error;
};

void zone_monitor_init(struct zone_monitor *m, uint8_t self, uint32_t now_ms);
/* Record per bus BEFORE duplicate filtering, or the second bus looks silent. */
void zone_monitor_heartbeat(struct zone_monitor *m, uint8_t zone, unsigned bus, uint32_t now_ms);
/* Any frame received from another node on this bus, valid or not. */
void zone_monitor_traffic(struct zone_monitor *m, unsigned bus, uint32_t now_ms);
/* A valid in-range CTRL arrived. */
void zone_monitor_ctrl(struct zone_monitor *m);
/* Relay gate: true while `zone`'s heartbeat on `bus` is under BUS_SILENT_MS old.
 * N2 forwards only frames whose origin is absent from the destination bus. */
bool zone_monitor_present(const struct zone_monitor *m, uint8_t zone, unsigned bus,
                          uint32_t now_ms);
/* Lab 1 R3 error state: power-up in error; out once both peers are alive on
 * some bus and a valid CTRL has arrived; in on a latch, a failed peer or isolation. */
struct zone_health zone_monitor_evaluate(const struct zone_monitor *m, uint32_t now_ms);
/* Milliseconds until a bus with traffic reaches BUS_SILENT_MS, or UINT32_MAX.
 * Dispatch waits on it so DEG_x lights at exactly 60 ms, not on the next HB_MON. */
uint32_t zone_monitor_next_change_ms(const struct zone_monitor *m, uint32_t now_ms);
#endif
```
